VERSION 5.7 ;
  NOWIREEXTENSIONATPIN ON ;
  DIVIDERCHAR "/" ;
  BUSBITCHARS "[]" ;
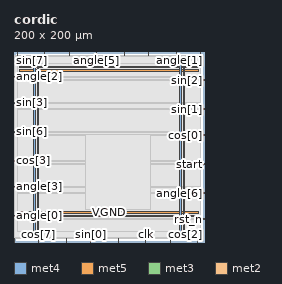
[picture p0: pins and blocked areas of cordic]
MACRO cordic
  CLASS BLOCK ;
  FOREIGN cordic ;
  ORIGIN 0.000 0.000 ;
  SIZE 200.000 BY 200.000 ;
  PIN VGND
    DIRECTION INOUT ;
    USE GROUND ;
    PORT
      LAYER met4 ;
        RECT 24.340 10.640 25.940 187.920 ;
    END
    PORT
      LAYER met4 ;
        RECT 177.940 10.640 179.540 187.920 ;
    END
    PORT
      LAYER met5 ;
        RECT 5.280 30.030 194.360 31.630 ;
    END
    PORT
      LAYER met5 ;
        RECT 5.280 183.210 194.360 184.810 ;
    END
  END VGND
  PIN VPWR
    DIRECTION INOUT ;
    USE POWER ;
    PORT
      LAYER met4 ;
        RECT 21.040 10.640 22.640 187.920 ;
    END
    PORT
      LAYER met4 ;
        RECT 174.640 10.640 176.240 187.920 ;
    END
    PORT
      LAYER met5 ;
        RECT 5.280 26.730 194.360 28.330 ;
    END
    PORT
      LAYER met5 ;
        RECT 5.280 179.910 194.360 181.510 ;
    END
  END VPWR
  PIN angle[0]
    DIRECTION INPUT ;
    USE SIGNAL ;
    ANTENNAGATEAREA 0.213000 ;
    PORT
      LAYER met3 ;
        RECT 0.000 27.240 4.000 27.840 ;
    END
  END angle[0]
  PIN angle[1]
    DIRECTION INPUT ;
    USE SIGNAL ;
    ANTENNAGATEAREA 0.159000 ;
    PORT
      LAYER met2 ;
        RECT 196.510 196.000 196.790 200.000 ;
    END
  END angle[1]
  PIN angle[2]
    DIRECTION INPUT ;
    USE SIGNAL ;
    ANTENNAGATEAREA 0.213000 ;
    PORT
      LAYER met3 ;
        RECT 0.000 173.440 4.000 174.040 ;
    END
  END angle[2]
  PIN angle[3]
    DIRECTION INPUT ;
    USE SIGNAL ;
    ANTENNAGATEAREA 0.213000 ;
    PORT
      LAYER met3 ;
        RECT 0.000 57.840 4.000 58.440 ;
    END
  END angle[3]
  PIN angle[4]
    DIRECTION INPUT ;
    USE SIGNAL ;
    ANTENNAGATEAREA 0.196500 ;
    PORT
      LAYER met2 ;
        RECT 58.050 196.000 58.330 200.000 ;
    END
  END angle[4]
  PIN angle[5]
    DIRECTION INPUT ;
    USE SIGNAL ;
    ANTENNAGATEAREA 0.196500 ;
    PORT
      LAYER met2 ;
        RECT 87.030 196.000 87.310 200.000 ;
    END
  END angle[5]
  PIN angle[6]
    DIRECTION INPUT ;
    USE SIGNAL ;
    ANTENNAGATEAREA 0.247500 ;
    PORT
      LAYER met3 ;
        RECT 196.000 51.040 200.000 51.640 ;
    END
  END angle[6]
  PIN angle[7]
    DIRECTION INPUT ;
    USE SIGNAL ;
    ANTENNAGATEAREA 0.213000 ;
    PORT
      LAYER met2 ;
        RECT 170.750 196.000 171.030 200.000 ;
    END
  END angle[7]
  PIN clk
    DIRECTION INPUT ;
    USE SIGNAL ;
    ANTENNAGATEAREA 0.852000 ;
    PORT
      LAYER met2 ;
        RECT 138.550 0.000 138.830 4.000 ;
    END
  END clk
  PIN cos[0]
    DIRECTION OUTPUT TRISTATE ;
    USE SIGNAL ;
    ANTENNADIFFAREA 0.445500 ;
    PORT
      LAYER met3 ;
        RECT 196.000 112.240 200.000 112.840 ;
    END
  END cos[0]
  PIN cos[1]
    DIRECTION OUTPUT TRISTATE ;
    USE SIGNAL ;
    ANTENNADIFFAREA 0.795200 ;
    PORT
      LAYER met2 ;
        RECT 141.770 196.000 142.050 200.000 ;
    END
  END cos[1]
  PIN cos[2]
    DIRECTION OUTPUT TRISTATE ;
    USE SIGNAL ;
    ANTENNADIFFAREA 0.795200 ;
    PORT
      LAYER met2 ;
        RECT 193.290 0.000 193.570 4.000 ;
    END
  END cos[2]
  PIN cos[3]
    DIRECTION OUTPUT TRISTATE ;
    USE SIGNAL ;
    ANTENNADIFFAREA 0.795200 ;
    PORT
      LAYER met3 ;
        RECT 0.000 85.040 4.000 85.640 ;
    END
  END cos[3]
  PIN cos[4]
    DIRECTION OUTPUT TRISTATE ;
    USE SIGNAL ;
    ANTENNADIFFAREA 0.795200 ;
    PORT
      LAYER met2 ;
        RECT 32.290 196.000 32.570 200.000 ;
    END
  END cos[4]
  PIN cos[5]
    DIRECTION OUTPUT TRISTATE ;
    USE SIGNAL ;
    ANTENNADIFFAREA 0.795200 ;
    PORT
      LAYER met2 ;
        RECT 164.310 0.000 164.590 4.000 ;
    END
  END cos[5]
  PIN cos[6]
    DIRECTION OUTPUT TRISTATE ;
    USE SIGNAL ;
    ANTENNADIFFAREA 0.795200 ;
    PORT
      LAYER met2 ;
        RECT 0.090 0.000 0.370 4.000 ;
    END
  END cos[6]
  PIN cos[7]
    DIRECTION OUTPUT TRISTATE ;
    USE SIGNAL ;
    ANTENNADIFFAREA 0.795200 ;
    PORT
      LAYER met2 ;
        RECT 25.850 0.000 26.130 4.000 ;
    END
  END cos[7]
  PIN done
    DIRECTION OUTPUT TRISTATE ;
    USE SIGNAL ;
    ANTENNADIFFAREA 0.795200 ;
    PORT
      LAYER met2 ;
        RECT 54.830 0.000 55.110 4.000 ;
    END
  END done
  PIN rst_n
    DIRECTION INPUT ;
    USE SIGNAL ;
    ANTENNAGATEAREA 0.159000 ;
    PORT
      LAYER met3 ;
        RECT 196.000 23.840 200.000 24.440 ;
    END
  END rst_n
  PIN sin[0]
    DIRECTION OUTPUT TRISTATE ;
    USE SIGNAL ;
    ANTENNADIFFAREA 0.795200 ;
    PORT
      LAYER met2 ;
        RECT 80.590 0.000 80.870 4.000 ;
    END
  END sin[0]
  PIN sin[1]
    DIRECTION OUTPUT TRISTATE ;
    USE SIGNAL ;
    ANTENNADIFFAREA 0.445500 ;
    PORT
      LAYER met3 ;
        RECT 196.000 139.440 200.000 140.040 ;
    END
  END sin[1]
  PIN sin[2]
    DIRECTION OUTPUT TRISTATE ;
    USE SIGNAL ;
    ANTENNADIFFAREA 0.795200 ;
    PORT
      LAYER met3 ;
        RECT 196.000 170.040 200.000 170.640 ;
    END
  END sin[2]
  PIN sin[3]
    DIRECTION OUTPUT TRISTATE ;
    USE SIGNAL ;
    ANTENNADIFFAREA 0.795200 ;
    PORT
      LAYER met3 ;
        RECT 0.000 146.240 4.000 146.840 ;
    END
  END sin[3]
  PIN sin[4]
    DIRECTION OUTPUT TRISTATE ;
    USE SIGNAL ;
    ANTENNADIFFAREA 0.795200 ;
    PORT
      LAYER met2 ;
        RECT 116.010 196.000 116.290 200.000 ;
    END
  END sin[4]
  PIN sin[5]
    DIRECTION OUTPUT TRISTATE ;
    USE SIGNAL ;
    ANTENNADIFFAREA 0.795200 ;
    PORT
      LAYER met2 ;
        RECT 109.570 0.000 109.850 4.000 ;
    END
  END sin[5]
  PIN sin[6]
    DIRECTION OUTPUT TRISTATE ;
    USE SIGNAL ;
    ANTENNADIFFAREA 0.795200 ;
    PORT
      LAYER met3 ;
        RECT 0.000 115.640 4.000 116.240 ;
    END
  END sin[6]
  PIN sin[7]
    DIRECTION OUTPUT TRISTATE ;
    USE SIGNAL ;
    ANTENNADIFFAREA 0.795200 ;
    PORT
      LAYER met2 ;
        RECT 3.310 196.000 3.590 200.000 ;
    END
  END sin[7]
  PIN start
    DIRECTION INPUT ;
    USE SIGNAL ;
    ANTENNAGATEAREA 0.196500 ;
    PORT
      LAYER met3 ;
        RECT 196.000 81.640 200.000 82.240 ;
    END
  END start
  OBS
      LAYER li1 ;
        RECT 5.520 10.795 194.120 187.765 ;
      LAYER met1 ;
        RECT 0.070 10.640 196.810 187.920 ;
      LAYER met2 ;
        RECT 0.100 195.720 3.030 196.000 ;
        RECT 3.870 195.720 32.010 196.000 ;
        RECT 32.850 195.720 57.770 196.000 ;
        RECT 58.610 195.720 86.750 196.000 ;
        RECT 87.590 195.720 115.730 196.000 ;
        RECT 116.570 195.720 141.490 196.000 ;
        RECT 142.330 195.720 170.470 196.000 ;
        RECT 171.310 195.720 196.230 196.000 ;
        RECT 0.100 4.280 196.780 195.720 ;
        RECT 0.650 4.000 25.570 4.280 ;
        RECT 26.410 4.000 54.550 4.280 ;
        RECT 55.390 4.000 80.310 4.280 ;
        RECT 81.150 4.000 109.290 4.280 ;
        RECT 110.130 4.000 138.270 4.280 ;
        RECT 139.110 4.000 164.030 4.280 ;
        RECT 164.870 4.000 193.010 4.280 ;
        RECT 193.850 4.000 196.780 4.280 ;
      LAYER met3 ;
        RECT 3.990 174.440 196.000 187.845 ;
        RECT 4.400 173.040 196.000 174.440 ;
        RECT 3.990 171.040 196.000 173.040 ;
        RECT 3.990 169.640 195.600 171.040 ;
        RECT 3.990 147.240 196.000 169.640 ;
        RECT 4.400 145.840 196.000 147.240 ;
        RECT 3.990 140.440 196.000 145.840 ;
        RECT 3.990 139.040 195.600 140.440 ;
        RECT 3.990 116.640 196.000 139.040 ;
        RECT 4.400 115.240 196.000 116.640 ;
        RECT 3.990 113.240 196.000 115.240 ;
        RECT 3.990 111.840 195.600 113.240 ;
        RECT 3.990 86.040 196.000 111.840 ;
        RECT 4.400 84.640 196.000 86.040 ;
        RECT 3.990 82.640 196.000 84.640 ;
        RECT 3.990 81.240 195.600 82.640 ;
        RECT 3.990 58.840 196.000 81.240 ;
        RECT 4.400 57.440 196.000 58.840 ;
        RECT 3.990 52.040 196.000 57.440 ;
        RECT 3.990 50.640 195.600 52.040 ;
        RECT 3.990 28.240 196.000 50.640 ;
        RECT 4.400 26.840 196.000 28.240 ;
        RECT 3.990 24.840 196.000 26.840 ;
        RECT 3.990 23.440 195.600 24.840 ;
        RECT 3.990 10.715 196.000 23.440 ;
      LAYER met4 ;
        RECT 75.735 34.175 144.145 112.705 ;
  END
END cordic
END LIBRARY

